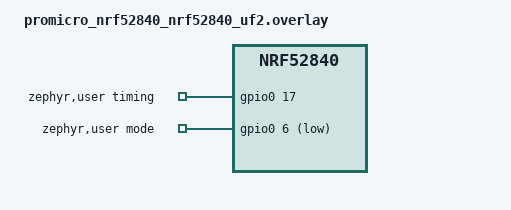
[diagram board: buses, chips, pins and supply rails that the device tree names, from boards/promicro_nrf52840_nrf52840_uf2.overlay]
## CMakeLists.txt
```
cmake_minimum_required(VERSION 3.20.0)

# Board-independent USB functions (app.overlay is ignored when board overlays exist)
list(APPEND EXTRA_DTC_OVERLAY_FILE ${CMAKE_CURRENT_LIST_DIR}/usb.overlay)
list(APPEND EXTRA_DTC_OVERLAY_FILE ${CMAKE_CURRENT_LIST_DIR}/peripherals.overlay)

find_package(Zephyr REQUIRED HINTS $ENV{ZEPHYR_BASE})
project(xbx_dongle)

include(../common/build_id.cmake)
xbx_build_id(dongle)

target_sources(app PRIVATE src/main.c src/pairing.c src/radio.c src/usb.c src/xinput.c src/bridge.c src/leds.c
	src/configurator.c ../common/src/config_usb.c ../common/src/hid_pad.c ../common/src/hid_pid.c)
target_compile_definitions(app PRIVATE XBX_DEVICE=XBX_DEVICE_DONGLE) # image marker
zephyr_linker_sources(RODATA ../common/image_marker.ld)
target_include_directories(app PRIVATE ${CMAKE_CURRENT_SOURCE_DIR}/../common/include)
```

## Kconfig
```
menu "xbx-nrf dongle"

config XBX_USB_CONSOLE
	bool "USB serial console as a composite function"
	default y
	help
	  Adds the CDC ACM serial port (log console) next to the gamepad on the
	  dongle's USB device. On for development builds; release.conf turns it
	  off.

config XBX_PAIR_RSSI_MIN
	int "Weakest pairing request accepted, -dBm"
	range 20 100
	default 50
	help
	  Pairing requests received weaker than -<this> dBm are ignored, so
	  only a controller held close to the dongle pairs. Raise it if
	  pairing at arm's length fails.

endmenu

source "Kconfig.zephyr"
```

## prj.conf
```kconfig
# Radio: Enhanced ShockBurst
CONFIG_ESB=y
CONFIG_ESB_MAX_PAYLOAD_LENGTH=32
# per controller pipe (7): the ACK payload in flight + the next one queued,
# plus pairing answers
CONFIG_ESB_TX_FIFO_SIZE=24
CONFIG_CLOCK_CONTROL=y
CONFIG_ESB_CLOCK_INIT=y

CONFIG_GPIO=y
# LEDs (leds.c): brightness from the configurator
CONFIG_PWM=y

# Pairing: random address from the hardware RNG, stored with settings on NVS
CONFIG_ENTROPY_GENERATOR=y
CONFIG_FLASH=y
CONFIG_FLASH_MAP=y
CONFIG_NVS=y
CONFIG_SETTINGS=y
# factory reset restarts the dongle
CONFIG_REBOOT=y
# time slot frame clock (radio.c)
CONFIG_COUNTER=y

CONFIG_LOG=y

# USB: our own device (usb.c) instead of the board's CDC-ACM-at-boot device
CONFIG_USB_DEVICE_STACK_NEXT=y
CONFIG_CDC_ACM_SERIAL_INITIALIZE_AT_BOOT=n
CONFIG_HWINFO=y
# the console may be the CDC ACM port itself: its class can't log there
CONFIG_USBD_CDC_ACM_LOG_LEVEL_OFF=y
CONFIG_USBD_HID_SUPPORT=y
# the ~570-byte HID report descriptor (with PID) goes out in one control transfer
CONFIG_UDC_BUF_POOL_SIZE=2048
```

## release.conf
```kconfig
# Release builds (build.sh -r): gamepad only, no serial function, no logs.
CONFIG_XBX_USB_CONSOLE=n
CONFIG_LOG=n
CONFIG_NCS_BOOT_BANNER=n
CONFIG_BOOT_BANNER=n
CONFIG_PRINTK=n
CONFIG_CONSOLE=n
CONFIG_UART_CONSOLE=n
```

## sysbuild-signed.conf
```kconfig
# Release builds: MCUboot + ECDSA P-256 signed images.
# Use firmware/build-signed.sh, which passes the private key path on the command line.
SB_CONFIG_BOOTLOADER_MCUBOOT=y
SB_CONFIG_BOOT_SIGNATURE_TYPE_ECDSA_P256=y
```

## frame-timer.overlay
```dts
/*
 * Time slot frame clock (radio.c), added to every build via
 * EXTRA_DTC_OVERLAY_FILE in CMakeLists.txt. TIMER2 is used by ESB.
 */

&timer3 {
	status = "okay";
};
```

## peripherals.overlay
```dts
/*
 * Peripherals the dongle app needs on every board, added via
 * EXTRA_DTC_OVERLAY_FILE in CMakeLists.txt.
 */

/ {
	chosen {
		/* the plain RNG: enough for the pairing address, much smaller than CryptoCell */
		zephyr,entropy = &rng;
	};
};

/* time slot frame clock (radio.c); TIMER2 is used by ESB */
&timer3 {
	status = "okay";
};

/* unused (the RNG above replaces it); disabled so its driver isn't built */
&cryptocell {
	status = "disabled";
};
```

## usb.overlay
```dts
/*
 * Board-independent USB functions, added to every build via
 * EXTRA_DTC_OVERLAY_FILE in CMakeLists.txt (app.overlay would be ignored,
 * because board overlays exist).
 */

&zephyr_udc0 {
	hid_dev_0: hid_dev_0 {
		compatible = "zephyr,hid-device";
		label = "XBX-NRF Dongle";
		protocol-code = "none";
		in-report-size = <17>;
		in-polling-period-us = <1000>;
		/*
		 * Also the OUT endpoint's max packet size: keep it above the 6-byte
		 * report so each report is a short packet that ends its transfer.
		 */
		out-report-size = <64>;
		out-polling-period-us = <1000>; /* PID uploads send several reports in a row */
	};

	/* configurator channel (config_usb.c), in both modes */
	hid_dev_1: hid_dev_1 {
		compatible = "zephyr,hid-device";
		label = "XBX-NRF Config";
		protocol-code = "none";
		in-report-size = <64>;
		in-polling-period-us = <10000>;
		out-report-size = <64>;
		out-polling-period-us = <10000>;
	};
};
```

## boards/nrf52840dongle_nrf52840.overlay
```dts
/*
 * Nordic nRF52840 Dongle (PCA10059), the dongle prototype. The board already
 * defines SW1 (P1.06, pair button) and the LEDs (P0.06; RGB on P0.08, P1.09,
 * P0.12, also on pwm0), all active-low; here: the mode switch, and pairing on
 * SW1 with the RGB LED's blue (PWM, for the brightness setting).
 */

/ {
	aliases {
		pair-sw = &button0;
		pair-led = &blue_pwm_led;
	};

	zephyr,user {
		/* USB mode, read at boot: switch to GND = XInput, open = HID */
		mode-gpios = <&gpio0 29 (GPIO_ACTIVE_LOW | GPIO_PULL_UP)>;
	};
};
```

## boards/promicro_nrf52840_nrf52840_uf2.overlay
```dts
/*
 * Pro Micro nRF52840 (nice!nano clone). The USB serial console is already the
 * board default, so only the scope timing pin and the mode strap are added.
 *
 * P0.17 = the Pro Micro "D2" position (silkscreen "017" / "P0.17" on most clones).
 */

/ {
	/* pairing indicator: the on-board LED (P0.15); no button, pairs when unpaired */
	aliases {
		pair-led = &led0;
	};

	zephyr,user {
		/* scope timing pin: pulses on every received report */
		timing-gpios = <&gpio0 17 GPIO_ACTIVE_HIGH>;

		/* USB mode, read at boot: jumper to GND = XInput, open = HID */
		mode-gpios = <&gpio0 6 (GPIO_ACTIVE_LOW | GPIO_PULL_UP)>;
	};
};
```

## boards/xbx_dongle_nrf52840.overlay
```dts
/*
 * xbx-nrf dongle (custom board, boards/xbx/xbx_dongle/). The board's console
 * is the J3 UART; the app moves it to a USB serial function, as on the other
 * dongle boards.
 */

#include <../boards/common/usb/cdc_acm_serial.dtsi>

/ {
	zephyr,user {
		/* scope timing pin (TP4): pulses on every received report */
		timing-gpios = <&gpio0 17 GPIO_ACTIVE_HIGH>;

		/*
		 * USB mode, read at boot: SW3 to GND via 1 kΩ = XInput, open
		 * (internal pull-up) = HID
		 */
		mode-gpios = <&gpio1 9 (GPIO_ACTIVE_LOW | GPIO_PULL_UP)>;
	};
};
```

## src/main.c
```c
/*
 * xbx-nrf dongle firmware.
 *
 * The radio (radio.c) receives input reports from up to 4 controllers, one
 * pipe each, and answers with output reports in the ACK payload; main prints
 * link statistics per controller once per second. The bridge (bridge.c)
 * forwards the reports to USB (usb.c): the HID gamepad (hid_pad.c, hid_pid.c,
 * single-player) or the XInput receiver (xinput.c, one slot per controller),
 * chosen by the mode strap. The configurator channel (configurator.c) is
 * there in both modes. The console carries the logs in development builds.
 */

#include <zephyr/kernel.h>
#include <zephyr/logging/log.h>

#include <app_version.h>
#include <xbx_build_id.h>

#include "protocol.h"
#include "bridge.h"
#include "configurator.h"
#include "hid_pad.h"
#include "leds.h"
#include "pairing.h"
#include "radio.h"
#include "usb.h"

LOG_MODULE_REGISTER(dongle, LOG_LEVEL_INF);

int main(void)
{
	struct radio_stats prev = {0};
	int err;

	LOG_INF("xbx-nrf dongle v%s (%s), protocol v%d, tx %d dBm", APP_VERSION_STRING,
		XBX_BUILD_ID, XBX_PROTOCOL_VERSION, XBX_TX_POWER_DBM);

	/* first: its stored LED brightness applies from the first LED on */
	err = configurator_init();
	if (err) {
		LOG_ERR("configurator channel init failed: %d", err);
		return 0;
	}
	leds_init();

	if (usb_mode_get() == USB_MODE_HID) {
		err = hid_pad_init();
		if (err) {
			LOG_ERR("HID init failed: %d", err);
			return 0;
		}
	}

	err = pairing_init();
	if (err) {
		LOG_ERR("pairing init failed: %d", err);
		return 0;
	}

	err = usb_start();
	if (err) {
		LOG_ERR("USB start failed: %d", err);
		return 0;
	}

	err = radio_start();
	if (err) {
		LOG_ERR("radio start failed: %d", err);
		return 0;
	}

	bridge_start();

	while (true) {
		struct radio_stats now;

		k_sleep(K_SECONDS(1));
		radio_get_stats(&now);

		/* one line per controller heard this second */
		for (uint8_t link = 0; link < RADIO_LINKS; link++) {
			const struct radio_link_stats *n = &now.link[link];
			const struct radio_link_stats *p = &prev.link[link];
			uint32_t received = n->received - p->received;
			struct xbx_input_report in;

			if (received == 0) {
				continue;
			}
			radio_get_last_input(link, &in);
			/* ESB reports RSSI as a positive magnitude in dBm */
			LOG_INF("P%u rx %u/s  lost %u  rssi -%d dBm  slot %d/%u err %d us  | btn %04x "
				"L(%d,%d) R(%d,%d) LT %u RT %u",
				link + 1, received, n->lost - p->lost,
				(n->rssi_sum - p->rssi_sum) / (int32_t)received,
				n->slot == XBX_SLOT_NONE ? -1 : n->slot, now.frame_slots,
				n->sync_err_us, in.buttons,
				in.lx, in.ly, in.rx, in.ry, in.lt, in.rt);
		}
		if (now.bad != prev.bad || now.ack_queue_full != prev.ack_queue_full) {
			LOG_WRN("bad %u  ack-full %u", now.bad - prev.bad,
				now.ack_queue_full - prev.ack_queue_full);
		}
		prev = now;
	}
	return 0;
}
```

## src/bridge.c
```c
/*
 * Radio → USB bridge. The radio interrupt only stores the newest report per
 * controller and wakes this thread; converting and submitting happens here, in
 * thread context, as the USB stack requires.
 *
 * XInput mode: each connected controller (radio link with a time slot) gets
 * the first free receiver slot (player) on its first report and gives it back
 * on link loss. HID mode is single-player:
 * the first controller to link up drives the gamepad until it's lost, others
 * are ignored meanwhile; link loss sends a neutral report.
 *
 * Also the rumble mixer: with each radio report (1 kHz while linked) the host
 * output for that player (HID vendor report, or xpad's rumble and LED
 * commands) is combined with the PID engine's strength (HID player only), the
 * larger value wins, and the result goes into that controller's next ACK
 * payloads.
 */

#include <zephyr/kernel.h>
#include <zephyr/logging/log.h>

#include <zephyr/spinlock.h>

#include <string.h>

#include "bridge.h"
#include "hid_pad.h"
#include "hid_pid.h"
#include "leds.h"
#include "pairing.h"
#include "protocol.h"
#include "radio.h"
#include "usb.h"
#include "xinput.h"

LOG_MODULE_REGISTER(bridge, LOG_LEVEL_INF);

BUILD_ASSERT(RADIO_SLOTS_MAX <= XINPUT_SLOTS, "an XInput slot for every connected controller");

#define XSLOT_NONE 0xFF

/* No report for this long = link lost: release everything (docs/protocol.md) */
#define LINK_TIMEOUT_MS 1000
/* wake at least this often to notice lost links while others are quiet */
#define POLL_MS 100

#define BRIDGE_STACK_SIZE 1024
#define BRIDGE_PRIORITY   K_PRIO_COOP(2)

static K_THREAD_STACK_DEFINE(bridge_stack, BRIDGE_STACK_SIZE);
static struct k_thread bridge_thread_data;

struct player {
	bool up;
	uint8_t xslot;    /* XInput receiver slot, XSLOT_NONE = none */
	uint32_t last_ms; /* uptime of the last report */
	/* last host output for this player (USB thread) */
	uint8_t host_rumble[4];
	uint8_t host_led;
};

static struct player players[RADIO_LINKS];
static struct k_spinlock host_lock;
static bool xinput_mode;
static int hid_link = -1; /* HID mode: the link driving the gamepad, -1 = none */

/* HID vendor output report: for whichever controller drives the gamepad */
static void host_output(const uint8_t rumble[4], uint8_t led)
{
	k_spinlock_key_t key = k_spin_lock(&host_lock);

	if (hid_link >= 0) {
		memcpy(players[hid_link].host_rumble, rumble, 4);
		players[hid_link].host_led = led;
	}
	k_spin_unlock(&host_lock, key);
}

/* the player in an XInput slot, or NULL (call with host_lock held) */
static struct player *xslot_player(uint8_t xslot)
{
	for (uint8_t link = 0; link < RADIO_LINKS; link++) {
		if (players[link].xslot == xslot) {
			return &players[link];
		}
	}
	return NULL;
}

/* XInput: 2 motors */
static void xinput_rumble(uint8_t slot, uint8_t heavy, uint8_t weak)
{
	k_spinlock_key_t key = k_spin_lock(&host_lock);
	struct player *p = xslot_player(slot);

	if (p) {
		p->host_rumble[XBX_RUMBLE_HEAVY] = heavy;
		p->host_rumble[XBX_RUMBLE_WEAK] = weak;
	}
	k_spin_unlock(&host_lock, key);
}

/* the Guide LED has no player number: any pattern but 0 (off) is on */
static void xinput_led(uint8_t slot, uint8_t pattern)
{
	k_spinlock_key_t key = k_spin_lock(&host_lock);
	struct player *p = xslot_player(slot);

	if (p) {
		p->host_led = pattern ? 0xFF : 0;
	}
	k_spin_unlock(&host_lock, key);
}

/* first free XInput slot, or XSLOT_NONE */
static uint8_t xslot_take(struct player *p)
{
	k_spinlock_key_t key = k_spin_lock(&host_lock);

	for (uint8_t xs = 0; xs < XINPUT_SLOTS; xs++) {
		if (!xslot_player(xs)) {
			p->xslot = xs;
			break;
		}
	}
	k_spin_unlock(&host_lock, key);
	return p->xslot;
}

/* xpad sends this when Guide is held 5 s */
static void xinput_power_off(uint8_t slot)
{
	k_spinlock_key_t key = k_spin_lock(&host_lock);
	struct player *p = xslot_player(slot);
	int link = p ? p - players : -1;

	k_spin_unlock(&host_lock, key);
	if (link >= 0) {
		radio_power_off(link);
	}
}

static const struct xinput_callbacks xinput_cbs = {
	.rumble = xinput_rumble,
	.led = xinput_led,
	.power_off = xinput_power_off,
};

/* PID strength drives both main motors of the HID player; trigger motors are host-only */
static void output_update(uint8_t link)
{
	uint8_t rumble[4];
	uint8_t led;
	k_spinlock_key_t key = k_spin_lock(&host_lock);

	memcpy(rumble, players[link].host_rumble, sizeof(rumble));
	led = players[link].host_led;
	k_spin_unlock(&host_lock, key);

	if (!xinput_mode && link == hid_link) {
		uint8_t pid = hid_pid_strength(k_uptime_get_32());

		rumble[XBX_RUMBLE_HEAVY] = MAX(rumble[XBX_RUMBLE_HEAVY], pid);
		rumble[XBX_RUMBLE_WEAK] = MAX(rumble[XBX_RUMBLE_WEAK], pid);
	}
	radio_set_output(link, rumble, led);
}

static void link_report(uint8_t link, uint32_t now)
{
	struct player *p = &players[link];
	struct xbx_input_report in;

	p->last_ms = now;
	if (!p->up) {
		p->up = true;
		pairing_link_connected(link + 1);
		if (xinput_mode) {
			if (xslot_take(p) == XSLOT_NONE) {
				LOG_WRN("pipe %u: no XInput slot free", link + 1);
			} else {
				/* presence first: the host adds the gamepad */
				xinput_set_connected(p->xslot, true);
				leds_player(p->xslot, true);
			}
		}
		LOG_INF("pipe %u: link up%s", link + 1, xinput_mode ? "" : " (HID)");
		if (xinput_mode && p->xslot != XSLOT_NONE) {
			LOG_INF("pipe %u: player %u", link + 1, p->xslot + 1);
		}
	}
	if (!xinput_mode && hid_link < 0) {
		hid_link = link;
		leds_player(0, true);
		LOG_INF("pipe %u: drives the HID gamepad", link + 1);
	}

	radio_get_last_input(link, &in);
	if (xinput_mode) {
		if (p->xslot != XSLOT_NONE) {
			xinput_update(p->xslot, &in);
		}
	} else if (link == hid_link) {
		struct hid_pad_state state;

		hid_pad_from_radio(&in, &state);
		hid_pad_update(&state);
	}
	output_update(link);
}

static void link_lost(uint8_t link)
{
	static const uint8_t off[4];
	struct player *p = &players[link];
	k_spinlock_key_t key;

	p->up = false;
	if (xinput_mode) {
		if (p->xslot != XSLOT_NONE) {
			xinput_set_connected(p->xslot, false);
			leds_player(p->xslot, false);
		}
	} else if (link == hid_link) {
		const struct hid_pad_state neutral = {
			.hat = HID_PAD_HAT_CENTERED,
			.battery = HID_PAD_BATTERY_UNKNOWN,
		};

		hid_pad_update(&neutral);
		hid_pid_stop_all();
		leds_player(0, false);
	}

	/* don't resume stale rumble when the controller reconnects */
	key = k_spin_lock(&host_lock);
	memset(p->host_rumble, 0, sizeof(p->host_rumble));
	p->host_led = 0;
	p->xslot = XSLOT_NONE;
	if (link == hid_link) {
		hid_link = -1; /* the next controller to report takes over */
	}
	k_spin_unlock(&host_lock, key);
	radio_set_output(link, off, 0);
	radio_link_lost(link);

	LOG_INF("pipe %u: link lost, %s", link + 1,
		xinput_mode ? "player disconnected" : "rumble off");
}

static void bridge_thread(void *p1, void *p2, void *p3)
{
	xinput_mode = usb_mode_get() == USB_MODE_XINPUT;
	radio_set_xinput(xinput_mode);

	while (true) {
		uint32_t fresh = radio_wait_input(K_MSEC(POLL_MS));
		uint32_t now = k_uptime_get_32();

		for (uint8_t link = 0; link < RADIO_LINKS; link++) {
			if (fresh & BIT(link)) {
				link_report(link, now);
			} else if (players[link].up &&
				   now - players[link].last_ms >= LINK_TIMEOUT_MS) {
				link_lost(link);
			}
		}
	}
}

void bridge_start(void)
{
	for (uint8_t link = 0; link < RADIO_LINKS; link++) {
		players[link].xslot = XSLOT_NONE;
	}
	hid_pad_set_output_cb(host_output);
	xinput_set_callbacks(&xinput_cbs);
	k_thread_create(&bridge_thread_data, bridge_stack, K_THREAD_STACK_SIZEOF(bridge_stack),
			bridge_thread, NULL, NULL, NULL, BRIDGE_PRIORITY, 0, K_NO_WAIT);
	k_thread_name_set(&bridge_thread_data, "bridge");
}
```

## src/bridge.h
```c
/*
 * Radio ↔ USB bridge: forwards each controller's reports to its XInput slot
 * (or the first one's to the HID gamepad), handles link up/loss, and routes
 * host output (rumble, LED), mixed with PID force feedback, to the radio.
 */

#ifndef XBX_DONGLE_BRIDGE_H_
#define XBX_DONGLE_BRIDGE_H_

/* Start the bridge thread; call after radio_start() and usb_start(). */
void bridge_start(void);

#endif /* XBX_DONGLE_BRIDGE_H_ */
```

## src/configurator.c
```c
/*
 * Configurator commands on the dongle (see configurator.h). Settings: the LED
 * levels, key "cfg/leds", saved 1 s after the last change; other "cfg/" keys
 * (older firmware) are deleted at boot. Requests, the save and the flush all
 * run on the system work queue.
 */

#include <zephyr/kernel.h>
#include <zephyr/logging/log.h>
#include <zephyr/settings/settings.h>

#include <errno.h>
#include <stdio.h>
#include <string.h>

#include "config_usb.h"
#include "configurator.h"
#include "led_level.h"
#include "leds.h"
#include "pairing.h"
#include "usb.h"

LOG_MODULE_REGISTER(configurator, LOG_LEVEL_INF);

#define LEDS_KEY   "cfg/leds"
#define SAVE_DELAY K_SECONDS(1)

static const struct cfg_usb_dongle_leds leds_default = {
	.pair = XBX_LED_DEFAULT,
	.player = XBX_LED_DEFAULT,
	.power = XBX_LED_DEFAULT,
	.on = CFG_USB_LEDS_PLAYER_ON | CFG_USB_LEDS_POWER_ON,
};

static struct cfg_usb_dongle_leds leds_cfg = leds_default;
static char stale_key[24]; /* an unknown key seen while loading, deleted after */

static bool leds_valid(const struct cfg_usb_dongle_leds *c)
{
	return c->pair && c->player && c->power &&
	       !(c->on & ~(CFG_USB_LEDS_PLAYER_ON | CFG_USB_LEDS_POWER_ON));
}

static void leds_apply(void)
{
	struct leds_levels l = {
		.pair = leds_cfg.pair,
		.player = (leds_cfg.on & CFG_USB_LEDS_PLAYER_ON) ? leds_cfg.player : 0,
		.power = (leds_cfg.on & CFG_USB_LEDS_POWER_ON) ? leds_cfg.power : 0,
	};

	leds_set_levels(&l);
}

static int cfg_load(const char *name, size_t len, settings_read_cb read_cb, void *cb_arg)
{
	struct cfg_usb_dongle_leds c;

	if (strcmp(name, "leds") != 0) {
		/* not deleted here: the load is still reading the storage */
		snprintf(stale_key, sizeof(stale_key), "cfg/%s", name);
		return 0;
	}
	if (len == sizeof(c) && read_cb(cb_arg, &c, sizeof(c)) == sizeof(c) && leds_valid(&c)) {
		leds_cfg = c;
	}
	return 0;
}

SETTINGS_STATIC_HANDLER_DEFINE(cfg, "cfg", NULL, cfg_load, NULL, NULL);

static void save_fn(struct k_work *work)
{
	ARG_UNUSED(work);
	if (settings_save_one(LEDS_KEY, &leds_cfg, sizeof(leds_cfg))) {
		LOG_WRN("LED levels not saved");
	}
}

static K_WORK_DELAYABLE_DEFINE(save_work, save_fn);

static int setting_get(uint8_t id, uint8_t *value, size_t size)
{
	if (id != CFG_USB_SETTING_DONGLE_LEDS) {
		return -ENOTSUP;
	}
	if (size < sizeof(leds_cfg)) {
		return -EINVAL;
	}
	memcpy(value, &leds_cfg, sizeof(leds_cfg));
	return sizeof(leds_cfg);
}

/*
 * What a change shows: the groups whose level changed, and the player LEDs
 * switched on (often dark: no controller). The pair LED is off outside
 * pairing, so its slider needs this most.
 */
static uint8_t preview_groups(const struct cfg_usb_dongle_leds *old,
			      const struct cfg_usb_dongle_leds *new)
{
	uint8_t g = 0;

	if (new->pair != old->pair) {
		g |= LEDS_PREVIEW_PAIR;
	}
	if (new->player != old->player || (new->on & ~old->on & CFG_USB_LEDS_PLAYER_ON)) {
		g |= LEDS_PREVIEW_PLAYER;
	}
	if (new->power != old->power) {
		g |= LEDS_PREVIEW_POWER;
	}
	return g;
}

static int setting_set(uint8_t id, const uint8_t *value, size_t len)
{
	struct cfg_usb_dongle_leds c;

	if (id != CFG_USB_SETTING_DONGLE_LEDS) {
		return -ENOTSUP;
	}
	if (len < sizeof(c)) {
		return -EINVAL;
	}
	memcpy(&c, value, sizeof(c));
	if (!leds_valid(&c)) {
		return -EINVAL;
	}
	leds_preview(preview_groups(&leds_cfg, &c));
	leds_cfg = c;
	leds_apply();
	k_work_reschedule(&save_work, SAVE_DELAY);
	return 0;
}

static void flush(void)
{
	if (k_work_delayable_is_pending(&save_work)) {
		k_work_cancel_delayable(&save_work);
		save_fn(NULL);
	}
}

/* the restart follows */
static int factory_reset(uint8_t scope)
{
	if (scope & CFG_USB_RESET_CALIBRATION) {
		return -ENOTSUP;
	}
	if (scope & CFG_USB_RESET_SETTINGS) {
		k_work_cancel_delayable(&save_work);
		settings_delete(LEDS_KEY);
	}
	if (scope & CFG_USB_RESET_PAIRING) {
		pairing_forget();
	}
	return 0;
}

static const uint8_t setting_ids[] = {CFG_USB_SETTING_DONGLE_LEDS};

static const struct config_usb_app app = {
	.ids = setting_ids,
	.id_count = ARRAY_SIZE(setting_ids),
	.get = setting_get,
	.set = setting_set,
	.flush = flush,
	.factory_reset = factory_reset,
};

int configurator_init(void)
{
	int err = settings_subsys_init();

	if (!err) {
		err = settings_load_subtree("cfg");
	}
	if (!err && stale_key[0]) {
		LOG_INF("settings: deleting stale %s", stale_key);
		err = settings_delete(stale_key);
	}
	if (err) {
		LOG_WRN("settings: %d", err);
	}
	leds_apply();
	return config_usb_init(usb_mode_get(), &app);
}
```

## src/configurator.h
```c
/*
 * The dongle's part of the configurator channel (config_usb.h): the LED
 * levels setting and FACTORY_RESET (settings, pairing); INFO, BOOTLOADER and
 * REBOOT are config_usb.c's.
 */

#ifndef XBX_DONGLE_CONFIGURATOR_H_
#define XBX_DONGLE_CONFIGURATOR_H_

/* Load the settings (applies the LED levels), register the channel; call
 * before leds_init() and usb_start(). */
int configurator_init(void);

#endif /* XBX_DONGLE_CONFIGURATOR_H_ */
```

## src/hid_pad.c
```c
/*
 * Dongle HID gamepad on Zephyr's usbd_hid class.
 *
 * The class sends reports zero-copy, so the buffer being sent (tx_report) stays
 * untouched until input_report_done; newer states wait in `pending`, replacing
 * each other, and go out on the next completion.
 */

#include <zephyr/kernel.h>
#include <zephyr/logging/log.h>
#include <zephyr/spinlock.h>
#include <zephyr/usb/class/hid.h>
#include <zephyr/usb/class/usbd_hid.h>

#include <string.h>

#include "hid_pad.h"
#include "protocol.h"

LOG_MODULE_REGISTER(hid_pad, LOG_LEVEL_INF);

#define IN_REPORT_ID  1
#define OUT_REPORT_ID 2

/* Generic Desktop usages not named in zephyr/usb/class/hid.h */
#define GD_Z   0x32
#define GD_RX  0x33
#define GD_RY  0x34
#define GD_RZ  0x35
#define GD_HAT 0x39

/* Main item flags */
#define DATA_VAR_ABS      0x02
#define DATA_VAR_ABS_NULL 0x42
#define CONST             0x01

static const uint8_t report_desc[] = {
	HID_USAGE_PAGE(HID_USAGE_GEN_DESKTOP),
	HID_USAGE(HID_USAGE_GEN_DESKTOP_GAMEPAD),
	HID_COLLECTION(HID_COLLECTION_APPLICATION),
		HID_REPORT_ID(IN_REPORT_ID),

		/* buttons 1-16 */
		HID_USAGE_PAGE(HID_USAGE_GEN_BUTTON),
		HID_USAGE_MIN8(1),
		HID_USAGE_MAX8(16),
		HID_LOGICAL_MIN8(0),
		HID_LOGICAL_MAX8(1),
		HID_REPORT_SIZE(1),
		HID_REPORT_COUNT(16),
		HID_INPUT(DATA_VAR_ABS),

		/* hat switch: 0-7 over 0-315°, out of range = centred (null) */
		HID_USAGE_PAGE(HID_USAGE_GEN_DESKTOP),
		HID_USAGE(GD_HAT),
		HID_LOGICAL_MIN8(0),
		HID_LOGICAL_MAX8(7),
		HID_ITEM(HID_ITEM_TAG_PHYSICAL_MIN, HID_ITEM_TYPE_GLOBAL, 1), 0,
		HID_ITEM(HID_ITEM_TAG_PHYSICAL_MAX, HID_ITEM_TYPE_GLOBAL, 2), 0x3B, 0x01, /* 315 */
		HID_ITEM(HID_ITEM_TAG_UNIT, HID_ITEM_TYPE_GLOBAL, 1), 0x14, /* degrees */
		HID_REPORT_SIZE(4),
		HID_REPORT_COUNT(1),
		HID_INPUT(DATA_VAR_ABS_NULL),
		HID_ITEM(HID_ITEM_TAG_UNIT, HID_ITEM_TYPE_GLOBAL, 1), 0x00,
		HID_INPUT(CONST), /* 4 bits padding */

		/* sticks */
		HID_USAGE(HID_USAGE_GEN_DESKTOP_X),
		HID_USAGE(HID_USAGE_GEN_DESKTOP_Y),
		HID_USAGE(GD_RX),
		HID_USAGE(GD_RY),
		HID_LOGICAL_MIN16(0x00, 0x80), /* -32768 */
		HID_LOGICAL_MAX16(0xFF, 0x7F), /* 32767 */
		HID_ITEM(HID_ITEM_TAG_PHYSICAL_MAX, HID_ITEM_TYPE_GLOBAL, 0),
		HID_REPORT_SIZE(16),
		HID_REPORT_COUNT(4),
		HID_INPUT(DATA_VAR_ABS),

		/* triggers */
		HID_USAGE(GD_Z),
		HID_USAGE(GD_RZ),
		HID_LOGICAL_MIN8(0),
		HID_LOGICAL_MAX16(0xFF, 0x03), /* 1023 */
		HID_REPORT_COUNT(2),
		HID_INPUT(DATA_VAR_ABS),

		/* output: rumble heavy, light, LT, RT, Guide LED */
		HID_REPORT_ID(OUT_REPORT_ID),
		HID_USAGE_PAGE16(0xFF00),
		HID_USAGE(0x01),
		HID_LOGICAL_MIN8(0),
		HID_LOGICAL_MAX16(0xFF, 0x00), /* 255 */
		HID_REPORT_SIZE(8),
		HID_REPORT_COUNT(5),
		HID_OUTPUT(DATA_VAR_ABS),
	HID_END_COLLECTION,
};

struct in_report {
	uint8_t id;
	uint16_t buttons;
	uint8_t hat;  /* low nibble; high nibble padding */
	int16_t lx, ly, rx, ry;
	uint16_t lt, rt;
} __packed;

struct out_report {
	uint8_t id;
	uint8_t rumble[4];
	uint8_t led;
} __packed;

BUILD_ASSERT(sizeof(struct in_report) == DT_PROP(DT_NODELABEL(hid_dev_0), in_report_size));
BUILD_ASSERT(sizeof(struct out_report) < DT_PROP(DT_NODELABEL(hid_dev_0), out_report_size),
	     "OUT endpoint must be larger than the report (short packets end transfers)");

static const struct device *const hid_dev = DEVICE_DT_GET(DT_NODELABEL(hid_dev_0));

static struct in_report tx_report __aligned(sizeof(void *));
static struct in_report pending;
static bool have_pending;
static bool in_flight;
static bool iface_ready;
static uint32_t idle_duration;
static hid_pad_output_cb_t output_cb;

static void output_off(void);
static struct k_spinlock lock;

static void to_report(struct in_report *r, const struct hid_pad_state *s)
{
	r->id = IN_REPORT_ID;
	r->buttons = s->buttons;
	r->hat = s->hat & 0x0F;
	r->lx = s->lx;
	r->ly = s->ly;
	r->rx = s->rx;
	r->ry = s->ry;
	r->lt = s->lt;
	r->rt = s->rt;
}

static void try_submit(void)
{
	k_spinlock_key_t key = k_spin_lock(&lock);
	int err;

	if (!iface_ready || in_flight || !have_pending) {
		k_spin_unlock(&lock, key);
		return;
	}
	tx_report = pending;
	have_pending = false;
	in_flight = true;
	k_spin_unlock(&lock, key);

	err = hid_device_submit_report(hid_dev, sizeof(tx_report), (const uint8_t *)&tx_report);
	if (err) {
		key = k_spin_lock(&lock);
		in_flight = false;
		k_spin_unlock(&lock, key);
		LOG_WRN("submit failed: %d", err);
	}
}

void hid_pad_update(const struct hid_pad_state *state)
{
	k_spinlock_key_t key = k_spin_lock(&lock);

	to_report(&pending, state);
	have_pending = true;
	k_spin_unlock(&lock, key);

	try_submit();
}

static void pad_iface_ready(const struct device *dev, const bool ready)
{
	k_spinlock_key_t key = k_spin_lock(&lock);

	ARG_UNUSED(dev);
	iface_ready = ready;
	in_flight = false;
	k_spin_unlock(&lock, key);

	LOG_INF("interface %s", ready ? "ready" : "not ready");
	if (ready) {
		try_submit();
	} else {
		output_off(); /* host gone: stop rumble */
	}
}

static void pad_input_report_done(const struct device *dev, const uint8_t *const report)
{
	k_spinlock_key_t key = k_spin_lock(&lock);

	ARG_UNUSED(dev);
	ARG_UNUSED(report);
	in_flight = false;
	k_spin_unlock(&lock, key);

	try_submit();
}

static int pad_get_report(const struct device *dev, const uint8_t type, const uint8_t id,
			  const uint16_t len, uint8_t *const buf)
{
	k_spinlock_key_t key;

	ARG_UNUSED(dev);
	if (type != HID_REPORT_TYPE_INPUT || id != IN_REPORT_ID || len < sizeof(tx_report)) {
		return -ENOTSUP;
	}
	key = k_spin_lock(&lock);
	memcpy(buf, have_pending ? &pending : &tx_report, sizeof(tx_report));
	k_spin_unlock(&lock, key);
	return sizeof(tx_report);
}

void hid_pad_set_output_cb(hid_pad_output_cb_t cb)
{
	output_cb = cb;
}

static void output_off(void)
{
	static const uint8_t off[4];

	if (output_cb) {
		output_cb(off, 0);
	}
}

/* Output reports arrive via interrupt OUT or SET_REPORT */
static void handle_output(const uint8_t *buf, uint16_t len)
{
	const struct out_report *r = (const struct out_report *)buf;

	if (len != sizeof(*r) || r->id != OUT_REPORT_ID) {
		LOG_WRN("unexpected output report (len %u, id %u)", len, len ? buf[0] : 0);
		return;
	}
	LOG_DBG("output: rumble %u %u %u %u, LED %u", r->rumble[0], r->rumble[1], r->rumble[2],
		r->rumble[3], r->led);
	if (output_cb) {
		output_cb(r->rumble, r->led);
	}
}

static int pad_set_report(const struct device *dev, const uint8_t type, const uint8_t id,
			  const uint16_t len, const uint8_t *const buf)
{
	ARG_UNUSED(dev);
	ARG_UNUSED(id);
	if (type != HID_REPORT_TYPE_OUTPUT) {
		return -ENOTSUP;
	}
	handle_output(buf, len);
	return 0;
}

static void pad_output_report(const struct device *dev, const uint16_t len,
			      const uint8_t *const buf)
{
	ARG_UNUSED(dev);
	handle_output(buf, len);
}

static void pad_set_idle(const struct device *dev, const uint8_t id, const uint32_t duration)
{
	ARG_UNUSED(dev);
	ARG_UNUSED(id);
	idle_duration = duration;
}

static uint32_t pad_get_idle(const struct device *dev, const uint8_t id)
{
	ARG_UNUSED(dev);
	ARG_UNUSED(id);
	return idle_duration;
}

static const struct hid_device_ops pad_ops = {
	.iface_ready = pad_iface_ready,
	.get_report = pad_get_report,
	.set_report = pad_set_report,
	.set_idle = pad_set_idle,
	.get_idle = pad_get_idle,
	.input_report_done = pad_input_report_done,
	.output_report = pad_output_report,
};

static const struct {
	uint16_t radio;
	uint16_t hid;
} button_map[] = {
	{XBX_BTN_A, HID_PAD_BTN_A},         {XBX_BTN_B, HID_PAD_BTN_B},
	{XBX_BTN_X, HID_PAD_BTN_X},         {XBX_BTN_Y, HID_PAD_BTN_Y},
	{XBX_BTN_LB, HID_PAD_BTN_LB},       {XBX_BTN_RB, HID_PAD_BTN_RB},
	{XBX_BTN_VIEW, HID_PAD_BTN_VIEW},   {XBX_BTN_MENU, HID_PAD_BTN_MENU},
	{XBX_BTN_GUIDE, HID_PAD_BTN_GUIDE}, {XBX_BTN_LS, HID_PAD_BTN_LS},
	{XBX_BTN_RS, HID_PAD_BTN_RS},
};

/* index: bit 0 up, 1 down, 2 left, 3 right (opposites already cancelled) */
static const uint8_t hat_map[16] = {
	[0x0] = HID_PAD_HAT_CENTERED,
	[0x1] = 0, /* up */
	[0x9] = 1, /* up-right */
	[0x8] = 2, /* right */
	[0xA] = 3, /* down-right */
	[0x2] = 4, /* down */
	[0x6] = 5, /* down-left */
	[0x4] = 6, /* left */
	[0x5] = 7, /* up-left */
};

static uint8_t dpad_to_hat(uint16_t buttons)
{
	uint8_t d = 0;

	if ((buttons & XBX_BTN_DPAD_UP) && !(buttons & XBX_BTN_DPAD_DOWN)) {
		d |= 0x1;
	}
	if ((buttons & XBX_BTN_DPAD_DOWN) && !(buttons & XBX_BTN_DPAD_UP)) {
		d |= 0x2;
	}
	if ((buttons & XBX_BTN_DPAD_LEFT) && !(buttons & XBX_BTN_DPAD_RIGHT)) {
		d |= 0x4;
	}
	if ((buttons & XBX_BTN_DPAD_RIGHT) && !(buttons & XBX_BTN_DPAD_LEFT)) {
		d |= 0x8;
	}
	return d ? hat_map[d] : HID_PAD_HAT_CENTERED;
}

/* up = positive on the radio, down = positive in HID; -32768 would overflow */
static int16_t invert_axis(int16_t v)
{
	return (v == INT16_MIN) ? INT16_MAX : -v;
}

void hid_pad_from_radio(const struct xbx_input_report *in, struct hid_pad_state *out)
{
	uint16_t buttons = in->buttons;

	out->buttons = 0;
	for (size_t i = 0; i < ARRAY_SIZE(button_map); i++) {
		if (buttons & button_map[i].radio) {
			out->buttons |= button_map[i].hid;
		}
	}
	if (in->buttons_ext & XBX_BTN_EXT_SHARE) {
		out->buttons |= HID_PAD_BTN_SHARE;
	}

	out->hat = dpad_to_hat(buttons);
	out->lx = in->lx;
	out->ly = invert_axis(in->ly);
	out->rx = in->rx;
	out->ry = invert_axis(in->ry);
	out->lt = MIN(in->lt, 1023);
	out->rt = MIN(in->rt, 1023);
}

int hid_pad_init(void)
{
	const struct hid_pad_state neutral = {.hat = HID_PAD_HAT_CENTERED};

	if (!device_is_ready(hid_dev)) {
		return -ENODEV;
	}

	/* first report after the interface comes up: neutral */
	to_report(&pending, &neutral);
	have_pending = true;

	return hid_device_register(hid_dev, report_desc, sizeof(report_desc), &pad_ops);
}
```

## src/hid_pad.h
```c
/*
 * Dongle HID gamepad (1 player). Report layout: docs/protocol.md,
 * "USB HID mode". Newest state wins: updates replace any report the host
 * hasn't collected yet.
 */

#ifndef XBX_DONGLE_HID_PAD_H_
#define XBX_DONGLE_HID_PAD_H_

#include <stdint.h>

/* HID button n (1-based) is bit n-1; numbering matches Linux's gamepad codes */
#define HID_PAD_BTN(n)     (1u << ((n) - 1))
#define HID_PAD_BTN_A      HID_PAD_BTN(1)
#define HID_PAD_BTN_B      HID_PAD_BTN(2)
#define HID_PAD_BTN_X      HID_PAD_BTN(4)
#define HID_PAD_BTN_Y      HID_PAD_BTN(5)
#define HID_PAD_BTN_LB     HID_PAD_BTN(7)
#define HID_PAD_BTN_RB     HID_PAD_BTN(8)
#define HID_PAD_BTN_VIEW   HID_PAD_BTN(11)
#define HID_PAD_BTN_MENU   HID_PAD_BTN(12)
#define HID_PAD_BTN_GUIDE  HID_PAD_BTN(13)
#define HID_PAD_BTN_LS     HID_PAD_BTN(14)
#define HID_PAD_BTN_RS     HID_PAD_BTN(15)
#define HID_PAD_BTN_SHARE  HID_PAD_BTN(16)

/* hat: 0 = up, clockwise in 45° steps to 7 = up-left; 8 = centred */
#define HID_PAD_HAT_CENTERED 8

struct hid_pad_state {
	uint16_t buttons;  /* HID_PAD_BTN_* */
	uint8_t hat;       /* 0..7, HID_PAD_HAT_CENTERED */
	int16_t lx, ly;    /* HID convention: Y positive = down */
	int16_t rx, ry;
	uint16_t lt, rt;   /* 0..1023 */
};

/* Register with the HID class; call before usb_start(). */
int hid_pad_init(void);

/* Send a new state (thread context). */
void hid_pad_update(const struct hid_pad_state *state);

/*
 * Output report handler: rumble (heavy, light, LT, RT) and Guide LED, 0..255.
 * Also called with all zeros when the USB interface goes down.
 */
typedef void (*hid_pad_output_cb_t)(const uint8_t rumble[4], uint8_t led);
void hid_pad_set_output_cb(hid_pad_output_cb_t cb);

struct xbx_input_report;

/*
 * Radio report (XInput button layout, Y up = positive) to HID state: button
 * remap, D-pad to hat, Y axes inverted. Pair isn't reported to the PC.
 */
void hid_pad_from_radio(const struct xbx_input_report *in, struct hid_pad_state *out);

#endif /* XBX_DONGLE_HID_PAD_H_ */
```

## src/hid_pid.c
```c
/*
 * HID PID effect table and report handling (see hid_pid.h). Reports arrive in
 * the USB stack's thread; the table is guarded by a spinlock so the effect
 * engine can read it from another context.
 */

#include <zephyr/kernel.h>
#include <zephyr/logging/log.h>
#include <zephyr/spinlock.h>
#include <zephyr/sys/byteorder.h>

#include <string.h>

#include "hid_pid.h"

LOG_MODULE_REGISTER(hid_pid, LOG_LEVEL_INF);

/* nominal bytes per effect, only reported to the host */
#define EFFECT_BYTES 32

/* Report layouts: must match HID_PID_DESC field by field */
struct set_effect_report {
	uint8_t id;
	uint8_t block;
	uint8_t type; /* 1 = sine */
	uint16_t duration_ms;      /* 0xFFFF = infinite */
	uint16_t trigger_repeat_ms;
	uint16_t start_delay_ms;
	uint8_t gain;
	uint8_t trigger_button;
	uint8_t direction_enable; /* bit 0 */
	uint8_t direction;
} __packed;

struct set_envelope_report {
	uint8_t id;
	uint8_t block;
	uint8_t attack_level;
	uint8_t fade_level;
	uint16_t attack_ms;
	uint16_t fade_ms;
} __packed;

struct set_periodic_report {
	uint8_t id;
	uint8_t block;
	uint8_t magnitude;
	int8_t offset;
	uint8_t phase;
	uint16_t period_ms;
} __packed;

enum effect_op {
	OP_START = 1,
	OP_START_SOLO = 2,
	OP_STOP = 3,
};

struct effect_op_report {
	uint8_t id;
	uint8_t block;
	uint8_t op; /* enum effect_op */
	uint8_t loop_count;
} __packed;

struct block_report {
	uint8_t id;
	uint8_t block;
} __packed;

/* Device Control array index: usages 0x97..0x9C */
enum device_control {
	DC_ENABLE_ACTUATORS = 1,
	DC_DISABLE_ACTUATORS = 2,
	DC_STOP_ALL = 3,
	DC_RESET = 4,
	DC_PAUSE = 5,
	DC_CONTINUE = 6,
};

struct byte_report {
	uint8_t id;
	uint8_t value;
} __packed;

enum block_load_status {
	LOAD_SUCCESS = 1,
	LOAD_FULL = 2,
	LOAD_ERROR = 3,
};

struct block_load_report {
	uint8_t id;
	uint8_t block;
	uint8_t status; /* enum block_load_status */
	uint16_t ram_available;
} __packed;

struct pool_report {
	uint8_t id;
	uint16_t ram_size;
	uint8_t simultaneous_max;
	uint8_t flags; /* bit 0 device managed pool, bit 1 shared parameter blocks */
} __packed;

BUILD_ASSERT(sizeof(struct set_effect_report) == HID_PID_MAX_OUTPUT_LEN);

struct pid_effect {
	bool allocated;
	bool playing;
	uint8_t loops;  /* plays left, including the current one */
	uint8_t gain;
	uint8_t magnitude;
	int8_t offset;
	uint16_t period_ms;
	uint16_t duration_ms;
	uint16_t start_delay_ms;
	uint8_t attack_level, fade_level;
	uint16_t attack_ms, fade_ms;
	uint32_t start_ms; /* uptime at start */
};

static struct {
	struct pid_effect effects[HID_PID_MAX_EFFECTS]; /* block index n = effects[n - 1] */
	struct block_load_report block_load;            /* answer to the next GET */
	uint8_t device_gain;
	bool actuators_enabled;
	bool paused;
} pid;

static struct k_spinlock lock;

static uint8_t free_count(void)
{
	uint8_t n = 0;

	for (int i = 0; i < HID_PID_MAX_EFFECTS; i++) {
		n += !pid.effects[i].allocated;
	}
	return n;
}

/* block index → allocated effect, or NULL */
static struct pid_effect *effect_get(uint8_t block)
{
	if (block < 1 || block > HID_PID_MAX_EFFECTS || !pid.effects[block - 1].allocated) {
		return NULL;
	}
	return &pid.effects[block - 1];
}

static void stop_all(void)
{
	for (int i = 0; i < HID_PID_MAX_EFFECTS; i++) {
		pid.effects[i].playing = false;
	}
}

static void reset_locked(void)
{
	memset(pid.effects, 0, sizeof(pid.effects));
	pid.device_gain = 0xFF;
	pid.actuators_enabled = true;
	pid.paused = false;
}

void hid_pid_reset(void)
{
	k_spinlock_key_t key = k_spin_lock(&lock);

	reset_locked();
	k_spin_unlock(&lock, key);
}

static void create_effect(const uint8_t *buf, uint16_t len)
{
	struct block_load_report *r = &pid.block_load;

	r->id = HID_PID_ID_BLOCK_LOAD;
	r->block = 0;
	if (len != 2 || buf[1] != 1) {
		r->status = LOAD_ERROR;
	} else {
		r->status = LOAD_FULL;
		for (int i = 0; i < HID_PID_MAX_EFFECTS; i++) {
			if (!pid.effects[i].allocated) {
				memset(&pid.effects[i], 0, sizeof(pid.effects[i]));
				pid.effects[i].allocated = true;
				pid.effects[i].gain = 0xFF;
				r->block = i + 1;
				r->status = LOAD_SUCCESS;
				break;
			}
		}
	}
	r->ram_available = sys_cpu_to_le16(free_count() * EFFECT_BYTES);
}

static void effect_op(const struct effect_op_report *r)
{
	struct pid_effect *e = effect_get(r->block);

	if (!e) {
		return;
	}
	switch (r->op) {
	case OP_START_SOLO:
		stop_all();
		__fallthrough;
	case OP_START:
		e->playing = true;
		e->loops = MAX(r->loop_count, 1);
		e->start_ms = k_uptime_get_32();
		break;
	case OP_STOP:
		e->playing = false;
		break;
	default:
		break;
	}
}

static void device_control(uint8_t control)
{
	switch (control) {
	case DC_ENABLE_ACTUATORS:
		pid.actuators_enabled = true;
		break;
	case DC_DISABLE_ACTUATORS:
		pid.actuators_enabled = false;
		break;
	case DC_STOP_ALL:
		stop_all();
		break;
	case DC_RESET:
		reset_locked();
		break;
	case DC_PAUSE:
		pid.paused = true;
		break;
	case DC_CONTINUE:
		pid.paused = false;
		break;
	default:
		break;
	}
}

/* reports are copied first: the USB buffer needn't be aligned */
#define REPORT_COPY(type, var)                                                                   \
	type var;                                                                                \
	if (len != sizeof(var)) {                                                                \
		goto bad_len;                                                                    \
	}                                                                                        \
	memcpy(&var, buf, sizeof(var))

int hid_pid_output(const uint8_t *buf, uint16_t len)
{
	struct pid_effect *e;
	k_spinlock_key_t key;
	int ret = 0;

	if (len < 1) {
		return -ENOENT;
	}

	key = k_spin_lock(&lock);
	switch (buf[0]) {
	case HID_PID_ID_SET_EFFECT: {
		REPORT_COPY(struct set_effect_report, r);
		e = effect_get(r.block);
		if (e) {
			e->duration_ms = sys_le16_to_cpu(r.duration_ms);
			e->start_delay_ms = sys_le16_to_cpu(r.start_delay_ms);
			e->gain = r.gain;
		}
		LOG_DBG("set effect %u: duration %u delay %u gain %u", r.block,
			sys_le16_to_cpu(r.duration_ms), sys_le16_to_cpu(r.start_delay_ms), r.gain);
		break;
	}
	case HID_PID_ID_SET_ENVELOPE: {
		REPORT_COPY(struct set_envelope_report, r);
		e = effect_get(r.block);
		if (e) {
			e->attack_level = r.attack_level;
			e->fade_level = r.fade_level;
			e->attack_ms = sys_le16_to_cpu(r.attack_ms);
			e->fade_ms = sys_le16_to_cpu(r.fade_ms);
		}
		LOG_DBG("set envelope %u", r.block);
		break;
	}
	case HID_PID_ID_SET_PERIODIC: {
		REPORT_COPY(struct set_periodic_report, r);
		e = effect_get(r.block);
		if (e) {
			e->magnitude = r.magnitude;
			e->offset = r.offset;
			e->period_ms = sys_le16_to_cpu(r.period_ms);
		}
		LOG_DBG("set periodic %u: magnitude %u offset %d period %u", r.block, r.magnitude,
			r.offset, sys_le16_to_cpu(r.period_ms));
		break;
	}
	case HID_PID_ID_EFFECT_OP: {
		REPORT_COPY(struct effect_op_report, r);
		effect_op(&r);
		LOG_INF("effect %u: op %u loops %u", r.block, r.op, r.loop_count);
		break;
	}
	case HID_PID_ID_BLOCK_FREE: {
		REPORT_COPY(struct block_report, r);
		e = effect_get(r.block);
		if (e) {
			e->allocated = false;
			e->playing = false;
		}
		LOG_INF("free effect %u (%u free)", r.block, free_count());
		break;
	}
	case HID_PID_ID_DEVICE_CONTROL: {
		REPORT_COPY(struct byte_report, r);
		device_control(r.value);
		LOG_INF("device control %u", r.value);
		break;
	}
	case HID_PID_ID_DEVICE_GAIN: {
		REPORT_COPY(struct byte_report, r);
		pid.device_gain = r.value;
		LOG_INF("device gain %u", r.value);
		break;
	}
	default:
		ret = -ENOENT;
		break;
	}
	k_spin_unlock(&lock, key);
	return ret;

bad_len:
	k_spin_unlock(&lock, key);
	LOG_WRN("PID report 0x%02x: bad length %u", buf[0], len);
	return -EINVAL;
}

int hid_pid_set_feature(uint8_t id, const uint8_t *buf, uint16_t len)
{
	k_spinlock_key_t key;

	if (id != HID_PID_ID_CREATE_EFFECT) {
		return -ENOTSUP;
	}
	key = k_spin_lock(&lock);
	create_effect(buf, len);
	LOG_INF("create effect: block %u status %u", pid.block_load.block,
		pid.block_load.status);
	k_spin_unlock(&lock, key);
	return 0;
}

int hid_pid_get_feature(uint8_t id, uint8_t *buf, uint16_t len)
{
	k_spinlock_key_t key;

	switch (id) {
	case HID_PID_ID_BLOCK_LOAD:
		if (len < sizeof(struct block_load_report)) {
			return -EINVAL;
		}
		key = k_spin_lock(&lock);
		memcpy(buf, &pid.block_load, sizeof(struct block_load_report));
		k_spin_unlock(&lock, key);
		return sizeof(struct block_load_report);
	case HID_PID_ID_POOL: {
		const struct pool_report r = {
			.id = HID_PID_ID_POOL,
			.ram_size = sys_cpu_to_le16(HID_PID_MAX_EFFECTS * EFFECT_BYTES),
			.simultaneous_max = HID_PID_MAX_EFFECTS,
			.flags = BIT(0), /* device managed pool */
		};

		if (len < sizeof(r)) {
			return -EINVAL;
		}
		memcpy(buf, &r, sizeof(r));
		return sizeof(r);
	}
	default:
		return -ENOTSUP;
	}
}
```

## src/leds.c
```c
/*
 * Dongle LEDs (see leds.h). Found by node label, not alias: the PCA10059's
 * led1..led3 are its RGB LED. A mutex serializes the bridge thread (players)
 * and the system work queue (pairing, brightness).
 */

#include <zephyr/drivers/pwm.h>
#include <zephyr/kernel.h>

#include "led_level.h"
#include "leds.h"

enum led {
	LED_PAIR,
	LED_P1,
	LED_PWR = LED_P1 + 4,
	LED_COUNT,
};

#define PAIR_NODE DT_ALIAS(pair_led)

static const struct pwm_dt_spec specs[LED_COUNT] = {
#if DT_NODE_EXISTS(PAIR_NODE)
	[LED_PAIR] = PWM_DT_SPEC_GET(PAIR_NODE),
#endif
#if DT_NODE_EXISTS(DT_NODELABEL(p1_led))
	[LED_P1 + 0] = PWM_DT_SPEC_GET(DT_NODELABEL(p1_led)),
	[LED_P1 + 1] = PWM_DT_SPEC_GET(DT_NODELABEL(p2_led)),
	[LED_P1 + 2] = PWM_DT_SPEC_GET(DT_NODELABEL(p3_led)),
	[LED_P1 + 3] = PWM_DT_SPEC_GET(DT_NODELABEL(p4_led)),
#endif
	/* JP1 2–3: PWM-driven; with 1–2 it's always on regardless */
#if DT_NODE_EXISTS(DT_NODELABEL(pwr_led))
	[LED_PWR] = PWM_DT_SPEC_GET(DT_NODELABEL(pwr_led)),
#endif
};

static K_MUTEX_DEFINE(lock);
static struct leds_levels levels = {XBX_LED_DEFAULT, XBX_LED_DEFAULT, XBX_LED_DEFAULT};
static uint32_t lit;     /* bit per enum led */
static uint32_t preview; /* likewise: lit by leds_preview() */

#define PREVIEW_MS 1500

/* lock held */
static void apply(enum led i)
{
	const struct pwm_dt_spec *s = &specs[i];
	uint8_t l = i == LED_PAIR ? levels.pair : i == LED_PWR ? levels.power : levels.player;

	if (!s->dev || !pwm_is_ready_dt(s)) {
		return;
	}
	pwm_set_pulse_dt(s, ((lit | preview) & BIT(i)) ? xbx_led_pulse(s->period, l) : 0);
}

static void apply_all(void)
{
	for (int i = 0; i < LED_COUNT; i++) {
		apply(i);
	}
}

static void preview_end_fn(struct k_work *work)
{
	ARG_UNUSED(work);
	k_mutex_lock(&lock, K_FOREVER);
	preview = 0;
	apply_all();
	k_mutex_unlock(&lock);
}

static K_WORK_DELAYABLE_DEFINE(preview_end_work, preview_end_fn);

static void set(enum led i, bool on)
{
	k_mutex_lock(&lock, K_FOREVER);
	WRITE_BIT(lit, i, on);
	apply(i);
	k_mutex_unlock(&lock);
}

void leds_init(void)
{
	k_mutex_lock(&lock, K_FOREVER);
	lit = BIT(LED_PWR);
	apply_all();
	k_mutex_unlock(&lock);
}

void leds_player(uint8_t player, bool on)
{
	if (player < 4) {
		set(LED_P1 + player, on);
	}
}

void leds_pair(bool on)
{
	set(LED_PAIR, on);
}

void leds_set_levels(const struct leds_levels *new_levels)
{
	k_mutex_lock(&lock, K_FOREVER);
	levels = *new_levels;
	apply_all();
	k_mutex_unlock(&lock);
}

void leds_preview(uint8_t groups)
{
	k_mutex_lock(&lock, K_FOREVER);
	if (groups & LEDS_PREVIEW_PAIR) {
		preview |= BIT(LED_PAIR);
	}
	if (groups & LEDS_PREVIEW_PLAYER) {
		preview |= BIT(LED_P1) | BIT(LED_P1 + 1) | BIT(LED_P1 + 2) | BIT(LED_P1 + 3);
	}
	if (groups & LEDS_PREVIEW_POWER) {
		preview |= BIT(LED_PWR);
	}
	apply_all();
	k_mutex_unlock(&lock);
	k_work_reschedule(&preview_end_work, K_MSEC(PREVIEW_MS));
}
```

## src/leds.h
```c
/*
 * Dongle LEDs on PWM: the pair LED (alias pair-led), player LEDs P1..P4 and
 * the power LED (custom dongle; each a no-op where the board lacks it). Pn
 * lit = player n connected (HID mode: P1 only). Brightness per group
 * (led_level.h). Callable from any thread.
 */

#ifndef XBX_DONGLE_LEDS_H_
#define XBX_DONGLE_LEDS_H_

#include <stdbool.h>
#include <stdint.h>

/* levels 1–255, 0 = off (player and power only) */
struct leds_levels {
	uint8_t pair;
	uint8_t player;
	uint8_t power;
};

/* All LEDs off except the power LED. */
void leds_init(void);

/* Player 0..3. */
void leds_player(uint8_t player, bool on);

void leds_pair(bool on);

/* Applies at once. */
void leds_set_levels(const struct leds_levels *levels);

/* LEDS_PREVIEW_* */
#define LEDS_PREVIEW_PAIR   0x01
#define LEDS_PREVIEW_PLAYER 0x02 /* all four */
#define LEDS_PREVIEW_POWER  0x04

/*
 * Light these LEDs (at their level) until 1.5 s after the last call, so a
 * level change shows on LEDs that are off now.
 */
void leds_preview(uint8_t groups);

#endif /* XBX_DONGLE_LEDS_H_ */
```

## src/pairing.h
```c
/*
 * Dongle pairing (docs/protocol.md, "Pairing & multiple controllers"): the
 * dongle's own random address, created once and stored; the table of up to
 * PAIRING_PIPES paired controllers (pipe n = entry n - 1); and pairing mode,
 * entered with the pair button (alias pair-sw) or at boot while nothing is
 * paired. The pairing LED (leds_pair()) blinks fast meanwhile, then three
 * quick blinks when a controller is paired.
 *
 * The radio (radio.c) hands pairing messages over from its interrupt; the
 * answers are worked out and queued as ACK payloads from the system work
 * queue, where flash writes are allowed too.
 */

#ifndef XBX_DONGLE_PAIRING_H_
#define XBX_DONGLE_PAIRING_H_

#include <stdbool.h>
#include <stdint.h>

#include "protocol.h"

#define PAIRING_PIPES XBX_CTRL_PIPES /* controller pipes 1..7 */

struct pairing_addr {
	uint8_t base_addr1[4];
	uint8_t prefixes[PAIRING_PIPES]; /* pipes 1..7 */
};

/* Load (or create and store) address and table, set up button and LED. */
int pairing_init(void);

/* The dongle's address; valid after pairing_init(). */
const struct pairing_addr *pairing_addr(void);

/* The dongle's channel (chosen at first use); valid after pairing_init(). */
uint8_t pairing_channel(void);

/* Enter pairing mode (restarts the timeout if already in it). */
void pairing_start(const char *why);

bool pairing_active(void);

/* From the radio interrupt: a pairing request on pipe 0 (RSSI magnitude, dBm). */
void pairing_on_request(const struct xbx_pair_req *req, uint8_t rssi);

/* From the radio interrupt: a confirm on a controller pipe (1..7). */
void pairing_on_confirm(uint8_t pipe, const struct xbx_pair_confirm *confirm);

/* A paired controller's link came up: it becomes the most recently connected. */
void pairing_link_connected(uint8_t pipe);

/*
 * System work queue: forget the table, address and channel, LED solid; the
 * caller restarts soon after (nothing is saved until then).
 */
void pairing_forget(void);

#endif /* XBX_DONGLE_PAIRING_H_ */
```
